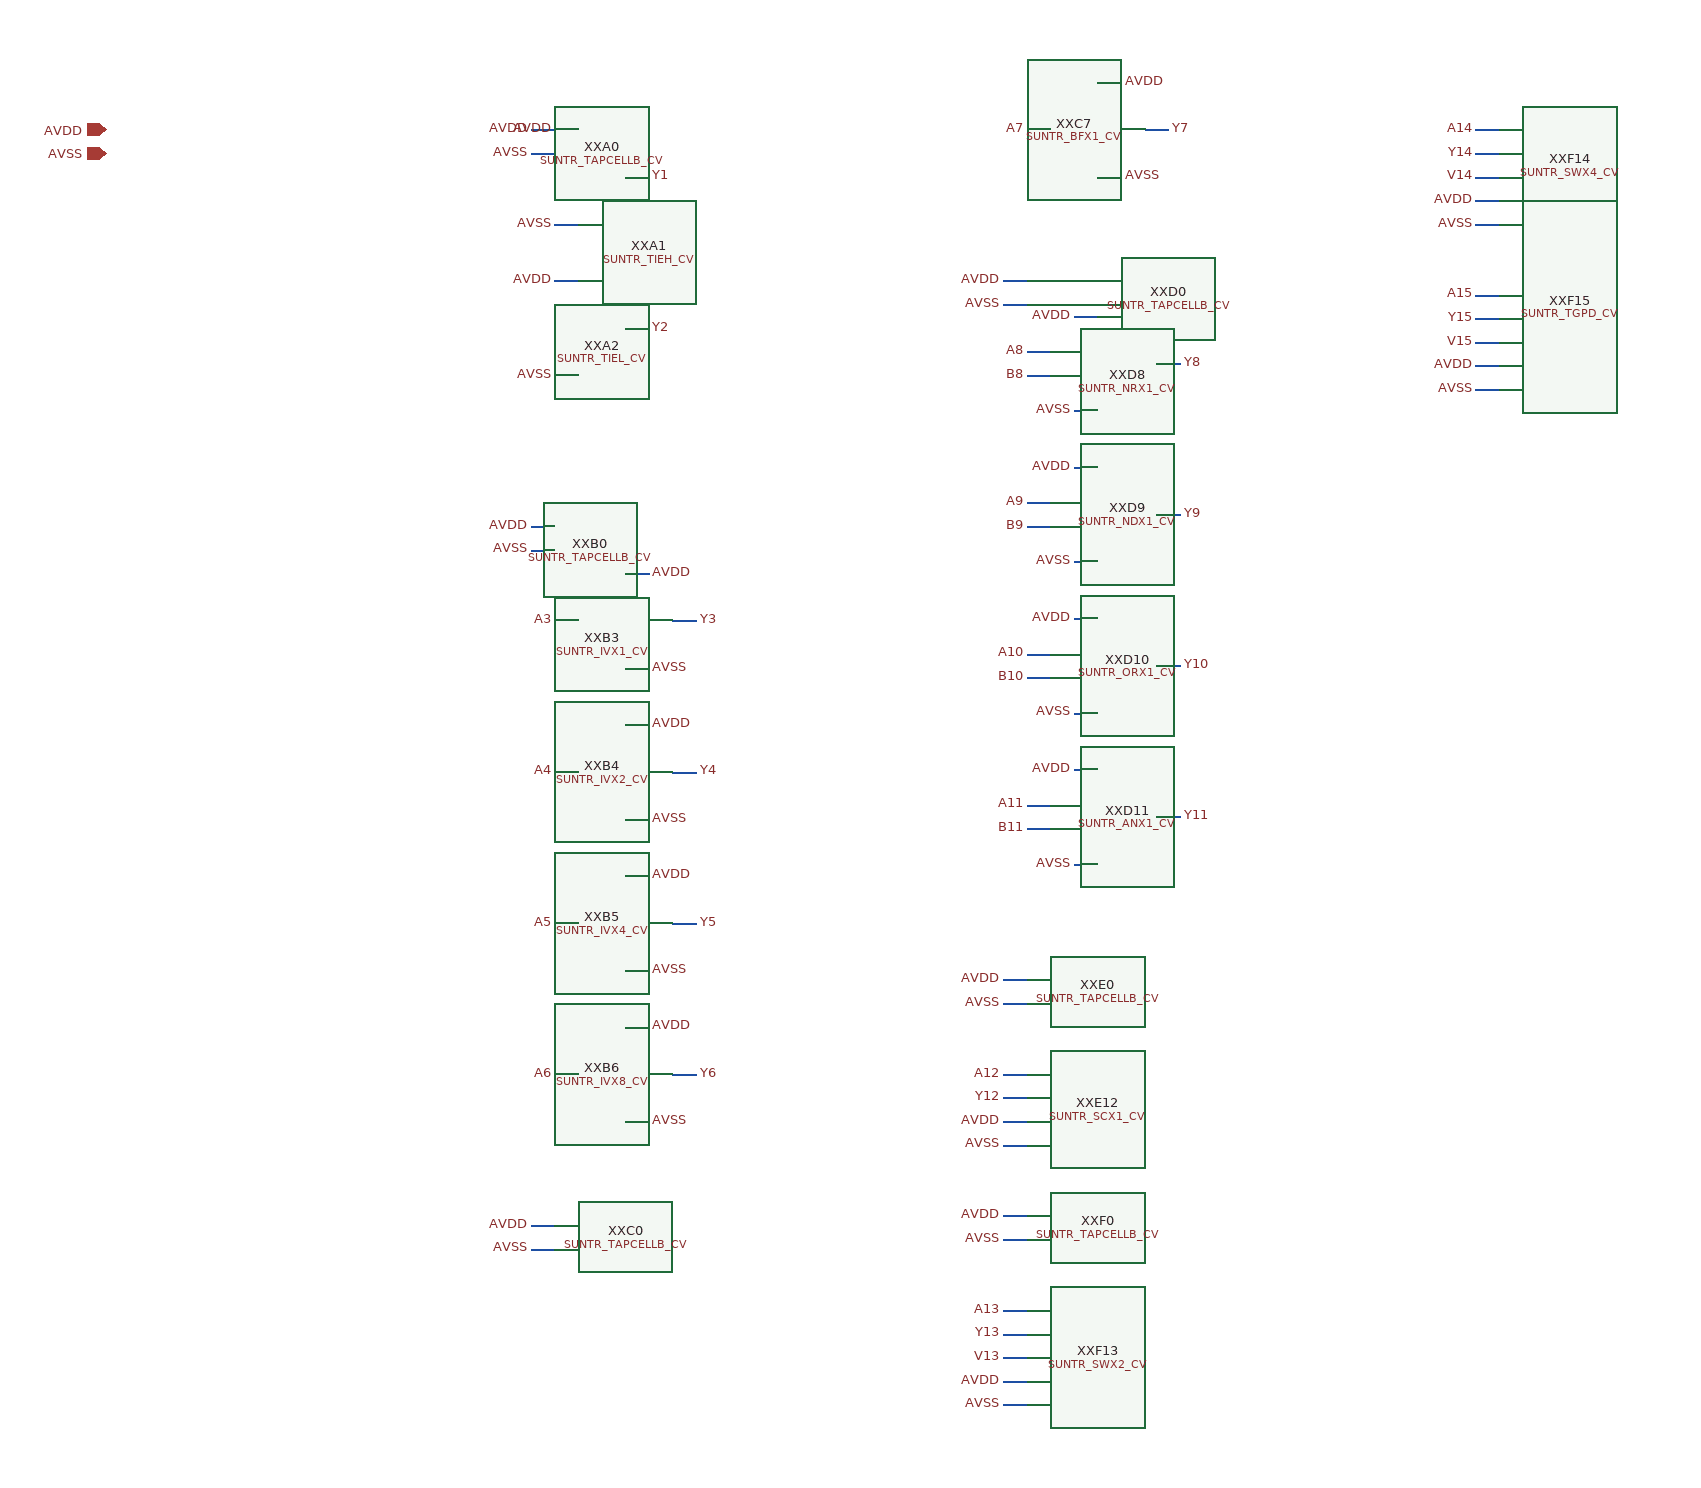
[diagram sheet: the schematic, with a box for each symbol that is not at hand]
v {xschem version=3.0.0 file_version=1.2 }
G {}
K {}
V {}
S {}
E {}
C {devices/iopin.sym} 0 0 0 0{name=p0 lab=AVDD}
C {devices/iopin.sym} 0 20 0 0{name=p1 lab=AVSS}
C {SUN_TR_SKY130NM/SUNTR_TAPCELLB_CV.sym} 400 0 0 0 {name=XXA0}
N 360.0 0.0 380.0 0.0{lab=AVDD}
C {devices/lab_pin.sym} 360.0 0.0 0 0  {name=l0 sig_type=std_logic lab=AVDD }
N 360.0 20.0 380.0 20.0{lab=AVSS}
C {devices/lab_pin.sym} 360.0 20.0 0 0  {name=l1 sig_type=std_logic lab=AVSS }
C {SUN_TR_SKY130NM/SUNTR_TIEH_CV.sym} 400 80 0 0 {name=XXA1}
N 460.0 40.0 440.0 40.0{lab=Y1}
C {devices/lab_pin.sym} 460.0 40.0 2 0  {name=l2 sig_type=std_logic lab=Y1 }
N 380.0 0.0 400.0 0.0{lab=AVDD}
C {devices/lab_pin.sym} 380.0 0.0 0 0  {name=l3 sig_type=std_logic lab=AVDD }
N 380.0 80.0 400.0 80.0{lab=AVSS}
C {devices/lab_pin.sym} 380.0 80.0 0 0  {name=l4 sig_type=std_logic lab=AVSS }
C {SUN_TR_SKY130NM/SUNTR_TIEL_CV.sym} 400 208.0 0 0 {name=XXA2}
N 460.0 168.0 440.0 168.0{lab=Y2}
C {devices/lab_pin.sym} 460.0 168.0 2 0  {name=l5 sig_type=std_logic lab=Y2 }
N 380.0 128.0 400.0 128.0{lab=AVDD}
C {devices/lab_pin.sym} 380.0 128.0 0 0  {name=l6 sig_type=std_logic lab=AVDD }
N 380.0 208.0 400.0 208.0{lab=AVSS}
C {devices/lab_pin.sym} 380.0 208.0 0 0  {name=l7 sig_type=std_logic lab=AVSS }
C {SUN_TR_SKY130NM/SUNTR_TAPCELLB_CV.sym} 400 336.0 0 0 {name=XXB0}
N 360.0 336.0 380.0 336.0{lab=AVDD}
C {devices/lab_pin.sym} 360.0 336.0 0 0  {name=l8 sig_type=std_logic lab=AVDD }
N 360.0 356.0 380.0 356.0{lab=AVSS}
C {devices/lab_pin.sym} 360.0 356.0 0 0  {name=l9 sig_type=std_logic lab=AVSS }
C {SUN_TR_SKY130NM/SUNTR_IVX1_CV.sym} 400 416.0 0 0 {name=XXB3}
N 380.0 416.0 400.0 416.0{lab=A3}
C {devices/lab_pin.sym} 380.0 416.0 0 0  {name=l10 sig_type=std_logic lab=A3 }
N 500.0 416.0 480.0 416.0{lab=Y3}
C {devices/lab_pin.sym} 500.0 416.0 2 0  {name=l11 sig_type=std_logic lab=Y3 }
N 460.0 376.0 440.0 376.0{lab=AVDD}
C {devices/lab_pin.sym} 460.0 376.0 2 0  {name=l12 sig_type=std_logic lab=AVDD }
N 460.0 456.0 440.0 456.0{lab=AVSS}
C {devices/lab_pin.sym} 460.0 456.0 2 0  {name=l13 sig_type=std_logic lab=AVSS }
C {SUN_TR_SKY130NM/SUNTR_IVX2_CV.sym} 400 544.0 0 0 {name=XXB4}
N 380.0 544.0 400.0 544.0{lab=A4}
C {devices/lab_pin.sym} 380.0 544.0 0 0  {name=l14 sig_type=std_logic lab=A4 }
N 500.0 544.0 480.0 544.0{lab=Y4}
C {devices/lab_pin.sym} 500.0 544.0 2 0  {name=l15 sig_type=std_logic lab=Y4 }
N 460.0 504.0 440.0 504.0{lab=AVDD}
C {devices/lab_pin.sym} 460.0 504.0 2 0  {name=l16 sig_type=std_logic lab=AVDD }
N 460.0 584.0 440.0 584.0{lab=AVSS}
C {devices/lab_pin.sym} 460.0 584.0 2 0  {name=l17 sig_type=std_logic lab=AVSS }
C {SUN_TR_SKY130NM/SUNTR_IVX4_CV.sym} 400 672.0 0 0 {name=XXB5}
N 380.0 672.0 400.0 672.0{lab=A5}
C {devices/lab_pin.sym} 380.0 672.0 0 0  {name=l18 sig_type=std_logic lab=A5 }
N 500.0 672.0 480.0 672.0{lab=Y5}
C {devices/lab_pin.sym} 500.0 672.0 2 0  {name=l19 sig_type=std_logic lab=Y5 }
N 460.0 632.0 440.0 632.0{lab=AVDD}
C {devices/lab_pin.sym} 460.0 632.0 2 0  {name=l20 sig_type=std_logic lab=AVDD }
N 460.0 712.0 440.0 712.0{lab=AVSS}
C {devices/lab_pin.sym} 460.0 712.0 2 0  {name=l21 sig_type=std_logic lab=AVSS }
C {SUN_TR_SKY130NM/SUNTR_IVX8_CV.sym} 400 800.0 0 0 {name=XXB6}
N 380.0 800.0 400.0 800.0{lab=A6}
C {devices/lab_pin.sym} 380.0 800.0 0 0  {name=l22 sig_type=std_logic lab=A6 }
N 500.0 800.0 480.0 800.0{lab=Y6}
C {devices/lab_pin.sym} 500.0 800.0 2 0  {name=l23 sig_type=std_logic lab=Y6 }
N 460.0 760.0 440.0 760.0{lab=AVDD}
C {devices/lab_pin.sym} 460.0 760.0 2 0  {name=l24 sig_type=std_logic lab=AVDD }
N 460.0 840.0 440.0 840.0{lab=AVSS}
C {devices/lab_pin.sym} 460.0 840.0 2 0  {name=l25 sig_type=std_logic lab=AVSS }
C {SUN_TR_SKY130NM/SUNTR_TAPCELLB_CV.sym} 400 928.0 0 0 {name=XXC0}
N 360.0 928.0 380.0 928.0{lab=AVDD}
C {devices/lab_pin.sym} 360.0 928.0 0 0  {name=l26 sig_type=std_logic lab=AVDD }
N 360.0 948.0 380.0 948.0{lab=AVSS}
C {devices/lab_pin.sym} 360.0 948.0 0 0  {name=l27 sig_type=std_logic lab=AVSS }
C {SUN_TR_SKY130NM/SUNTR_BFX1_CV.sym} 800 0 0 0 {name=XXC7}
N 780.0 0.0 800.0 0.0{lab=A7}
C {devices/lab_pin.sym} 780.0 0.0 0 0  {name=l28 sig_type=std_logic lab=A7 }
N 900.0 0.0 880.0 0.0{lab=Y7}
C {devices/lab_pin.sym} 900.0 0.0 2 0  {name=l29 sig_type=std_logic lab=Y7 }
N 860.0 -40.0 840.0 -40.0{lab=AVDD}
C {devices/lab_pin.sym} 860.0 -40.0 2 0  {name=l30 sig_type=std_logic lab=AVDD }
N 860.0 40.0 840.0 40.0{lab=AVSS}
C {devices/lab_pin.sym} 860.0 40.0 2 0  {name=l31 sig_type=std_logic lab=AVSS }
C {SUN_TR_SKY130NM/SUNTR_TAPCELLB_CV.sym} 800 128.0 0 0 {name=XXD0}
N 760.0 128.0 780.0 128.0{lab=AVDD}
C {devices/lab_pin.sym} 760.0 128.0 0 0  {name=l32 sig_type=std_logic lab=AVDD }
N 760.0 148.0 780.0 148.0{lab=AVSS}
C {devices/lab_pin.sym} 760.0 148.0 0 0  {name=l33 sig_type=std_logic lab=AVSS }
C {SUN_TR_SKY130NM/SUNTR_NRX1_CV.sym} 800 208.0 0 0 {name=XXD8}
N 780.0 188.0 800.0 188.0{lab=A8}
C {devices/lab_pin.sym} 780.0 188.0 0 0  {name=l34 sig_type=std_logic lab=A8 }
N 780.0 208.0 800.0 208.0{lab=B8}
C {devices/lab_pin.sym} 780.0 208.0 0 0  {name=l35 sig_type=std_logic lab=B8 }
N 910.0 198.0 890.0 198.0{lab=Y8}
C {devices/lab_pin.sym} 910.0 198.0 2 0  {name=l36 sig_type=std_logic lab=Y8 }
N 820.0 158.0 840.0 158.0{lab=AVDD}
C {devices/lab_pin.sym} 820.0 158.0 0 0  {name=l37 sig_type=std_logic lab=AVDD }
N 820.0 238.0 840.0 238.0{lab=AVSS}
C {devices/lab_pin.sym} 820.0 238.0 0 0  {name=l38 sig_type=std_logic lab=AVSS }
C {SUN_TR_SKY130NM/SUNTR_NDX1_CV.sym} 800 336.0 0 0 {name=XXD9}
N 780.0 316.0 800.0 316.0{lab=A9}
C {devices/lab_pin.sym} 780.0 316.0 0 0  {name=l39 sig_type=std_logic lab=A9 }
N 780.0 336.0 800.0 336.0{lab=B9}
C {devices/lab_pin.sym} 780.0 336.0 0 0  {name=l40 sig_type=std_logic lab=B9 }
N 910.0 326.0 890.0 326.0{lab=Y9}
C {devices/lab_pin.sym} 910.0 326.0 2 0  {name=l41 sig_type=std_logic lab=Y9 }
N 820.0 286.0 840.0 286.0{lab=AVDD}
C {devices/lab_pin.sym} 820.0 286.0 0 0  {name=l42 sig_type=std_logic lab=AVDD }
N 820.0 366.0 840.0 366.0{lab=AVSS}
C {devices/lab_pin.sym} 820.0 366.0 0 0  {name=l43 sig_type=std_logic lab=AVSS }
C {SUN_TR_SKY130NM/SUNTR_ORX1_CV.sym} 800 464.0 0 0 {name=XXD10}
N 780.0 444.0 800.0 444.0{lab=A10}
C {devices/lab_pin.sym} 780.0 444.0 0 0  {name=l44 sig_type=std_logic lab=A10 }
N 780.0 464.0 800.0 464.0{lab=B10}
C {devices/lab_pin.sym} 780.0 464.0 0 0  {name=l45 sig_type=std_logic lab=B10 }
N 910.0 454.0 890.0 454.0{lab=Y10}
C {devices/lab_pin.sym} 910.0 454.0 2 0  {name=l46 sig_type=std_logic lab=Y10 }
N 820.0 414.0 840.0 414.0{lab=AVDD}
C {devices/lab_pin.sym} 820.0 414.0 0 0  {name=l47 sig_type=std_logic lab=AVDD }
N 820.0 494.0 840.0 494.0{lab=AVSS}
C {devices/lab_pin.sym} 820.0 494.0 0 0  {name=l48 sig_type=std_logic lab=AVSS }
C {SUN_TR_SKY130NM/SUNTR_ANX1_CV.sym} 800 592.0 0 0 {name=XXD11}
N 780.0 572.0 800.0 572.0{lab=A11}
C {devices/lab_pin.sym} 780.0 572.0 0 0  {name=l49 sig_type=std_logic lab=A11 }
N 780.0 592.0 800.0 592.0{lab=B11}
C {devices/lab_pin.sym} 780.0 592.0 0 0  {name=l50 sig_type=std_logic lab=B11 }
N 910.0 582.0 890.0 582.0{lab=Y11}
C {devices/lab_pin.sym} 910.0 582.0 2 0  {name=l51 sig_type=std_logic lab=Y11 }
N 820.0 542.0 840.0 542.0{lab=AVDD}
C {devices/lab_pin.sym} 820.0 542.0 0 0  {name=l52 sig_type=std_logic lab=AVDD }
N 820.0 622.0 840.0 622.0{lab=AVSS}
C {devices/lab_pin.sym} 820.0 622.0 0 0  {name=l53 sig_type=std_logic lab=AVSS }
C {SUN_TR_SKY130NM/SUNTR_TAPCELLB_CV.sym} 800 720.0 0 0 {name=XXE0}
N 760.0 720.0 780.0 720.0{lab=AVDD}
C {devices/lab_pin.sym} 760.0 720.0 0 0  {name=l54 sig_type=std_logic lab=AVDD }
N 760.0 740.0 780.0 740.0{lab=AVSS}
C {devices/lab_pin.sym} 760.0 740.0 0 0  {name=l55 sig_type=std_logic lab=AVSS }
C {SUN_TR_SKY130NM/SUNTR_SCX1_CV.sym} 800 800.0 0 0 {name=XXE12}
N 760.0 800.0 780.0 800.0{lab=A12}
C {devices/lab_pin.sym} 760.0 800.0 0 0  {name=l56 sig_type=std_logic lab=A12 }
N 760.0 820.0 780.0 820.0{lab=Y12}
C {devices/lab_pin.sym} 760.0 820.0 0 0  {name=l57 sig_type=std_logic lab=Y12 }
N 760.0 840.0 780.0 840.0{lab=AVDD}
C {devices/lab_pin.sym} 760.0 840.0 0 0  {name=l58 sig_type=std_logic lab=AVDD }
N 760.0 860.0 780.0 860.0{lab=AVSS}
C {devices/lab_pin.sym} 760.0 860.0 0 0  {name=l59 sig_type=std_logic lab=AVSS }
C {SUN_TR_SKY130NM/SUNTR_TAPCELLB_CV.sym} 800 920.0 0 0 {name=XXF0}
N 760.0 920.0 780.0 920.0{lab=AVDD}
C {devices/lab_pin.sym} 760.0 920.0 0 0  {name=l60 sig_type=std_logic lab=AVDD }
N 760.0 940.0 780.0 940.0{lab=AVSS}
C {devices/lab_pin.sym} 760.0 940.0 0 0  {name=l61 sig_type=std_logic lab=AVSS }
C {SUN_TR_SKY130NM/SUNTR_SWX2_CV.sym} 800 1000.0 0 0 {name=XXF13}
N 760.0 1000.0 780.0 1000.0{lab=A13}
C {devices/lab_pin.sym} 760.0 1000.0 0 0  {name=l62 sig_type=std_logic lab=A13 }
N 760.0 1020.0 780.0 1020.0{lab=Y13}
C {devices/lab_pin.sym} 760.0 1020.0 0 0  {name=l63 sig_type=std_logic lab=Y13 }
N 760.0 1040.0 780.0 1040.0{lab=V13}
C {devices/lab_pin.sym} 760.0 1040.0 0 0  {name=l64 sig_type=std_logic lab=V13 }
N 760.0 1060.0 780.0 1060.0{lab=AVDD}
C {devices/lab_pin.sym} 760.0 1060.0 0 0  {name=l65 sig_type=std_logic lab=AVDD }
N 760.0 1080.0 780.0 1080.0{lab=AVSS}
C {devices/lab_pin.sym} 760.0 1080.0 0 0  {name=l66 sig_type=std_logic lab=AVSS }
C {SUN_TR_SKY130NM/SUNTR_SWX4_CV.sym} 1200 0 0 0 {name=XXF14}
N 1160.0 0.0 1180.0 0.0{lab=A14}
C {devices/lab_pin.sym} 1160.0 0.0 0 0  {name=l67 sig_type=std_logic lab=A14 }
N 1160.0 20.0 1180.0 20.0{lab=Y14}
C {devices/lab_pin.sym} 1160.0 20.0 0 0  {name=l68 sig_type=std_logic lab=Y14 }
N 1160.0 40.0 1180.0 40.0{lab=V14}
C {devices/lab_pin.sym} 1160.0 40.0 0 0  {name=l69 sig_type=std_logic lab=V14 }
N 1160.0 60.0 1180.0 60.0{lab=AVDD}
C {devices/lab_pin.sym} 1160.0 60.0 0 0  {name=l70 sig_type=std_logic lab=AVDD }
N 1160.0 80.0 1180.0 80.0{lab=AVSS}
C {devices/lab_pin.sym} 1160.0 80.0 0 0  {name=l71 sig_type=std_logic lab=AVSS }
C {SUN_TR_SKY130NM/SUNTR_TGPD_CV.sym} 1200 140 0 0 {name=XXF15}
N 1160.0 140.0 1180.0 140.0{lab=A15}
C {devices/lab_pin.sym} 1160.0 140.0 0 0  {name=l72 sig_type=std_logic lab=A15 }
N 1160.0 160.0 1180.0 160.0{lab=Y15}
C {devices/lab_pin.sym} 1160.0 160.0 0 0  {name=l73 sig_type=std_logic lab=Y15 }
N 1160.0 180.0 1180.0 180.0{lab=V15}
C {devices/lab_pin.sym} 1160.0 180.0 0 0  {name=l74 sig_type=std_logic lab=V15 }
N 1160.0 200.0 1180.0 200.0{lab=AVDD}
C {devices/lab_pin.sym} 1160.0 200.0 0 0  {name=l75 sig_type=std_logic lab=AVDD }
N 1160.0 220.0 1180.0 220.0{lab=AVSS}
C {devices/lab_pin.sym} 1160.0 220.0 0 0  {name=l76 sig_type=std_logic lab=AVSS }
